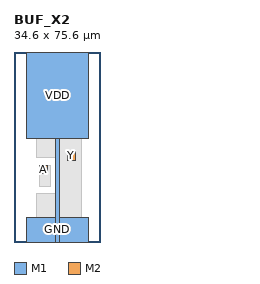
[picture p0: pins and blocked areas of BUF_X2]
MACRO BUF_X2
  CLASS CORE ;
  ORIGIN 0 0 ;
  SIZE 34.600 BY 75.600 ;
  SYMMETRY X Y ;
  SITE TR1um_access_site ;
  PIN VDD
    DIRECTION INOUT ;
    USE POWER ;
    PORT
      LAYER M1 ;
        RECT 16.400 0.000 18.200 41.000 ;
      LAYER M1 ;
        RECT 5.000 41.000 29.600 75.600 ;
    END
  END VDD
  PIN GND
    DIRECTION INOUT ;
    USE GROUND ;
    PORT
      LAYER M1 ;
        RECT 5.000 0.000 29.600 9.800 ;
    END
  END GND
  PIN A
    DIRECTION INPUT ;
    USE SIGNAL ;
    PORT
      LAYER M2 ;
        RECT 10.100 27.100 13.500 30.500 ;
    END
  END A
  PIN Y
    DIRECTION OUTPUT ;
    USE SIGNAL ;
    PORT
      LAYER M2 ;
        RECT 21.100 32.600 24.500 36.000 ;
    END
  END Y
  OBS
    LAYER M1 ;
      RECT 9.100 6.400 16.400 19.300 ;
    LAYER M1 ;
      RECT 10.100 22.200 14.500 30.500 ;
    LAYER M1 ;
      RECT 18.200 17.500 22.500 35.400 ;
    LAYER M1 ;
      RECT 9.100 33.600 16.400 51.200 ;
    LAYER M1 ;
      RECT 17.100 6.400 26.900 51.200 ;
    LAYER V1 ;
      RECT 11.100 28.100 12.500 29.500 ;
    LAYER V1 ;
      RECT 22.100 33.600 23.500 35.000 ;
  END
END BUF_X2
